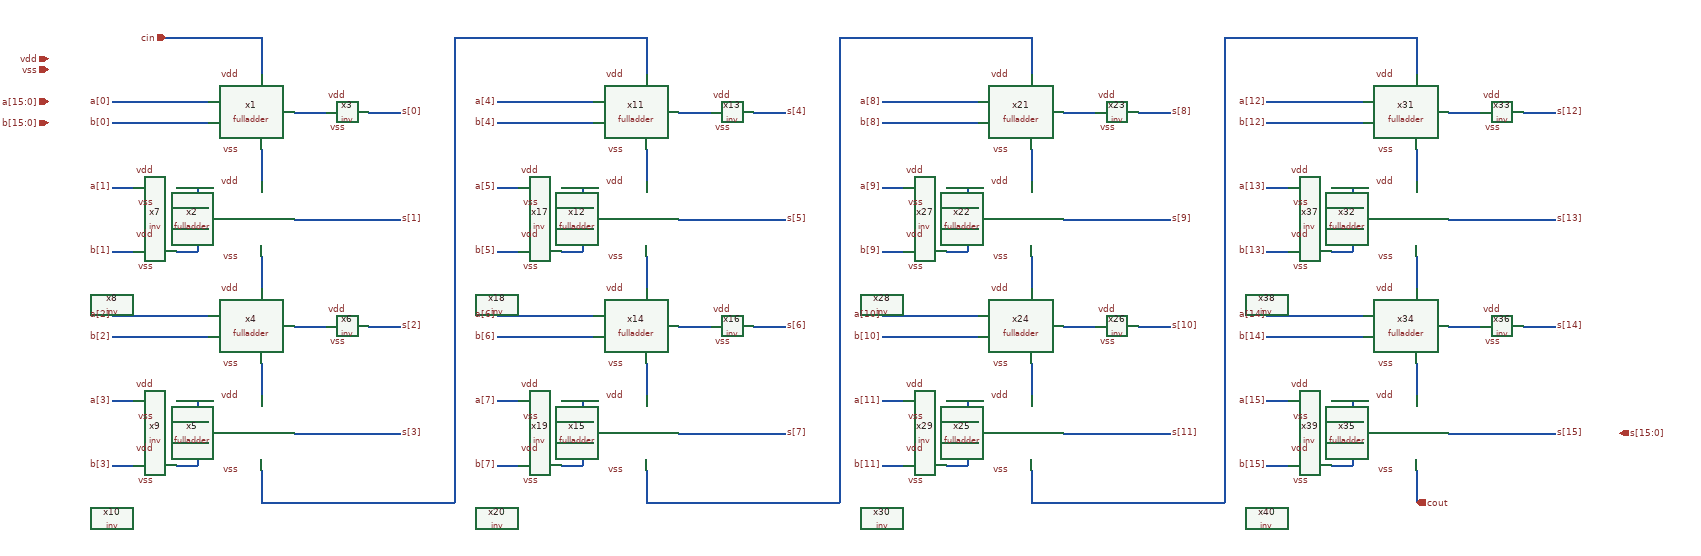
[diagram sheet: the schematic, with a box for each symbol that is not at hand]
v {xschem version=3.4.5 file_version=1.2
}
G {}
K {}
V {}
S {}
E {}
N 300 -460 300 -390 {
lab=cin}
N 120 -460 300 -460 {
lab=cin}
N 360 -320 420 -320 {
lab=#net1}
N 500 -320 560 -320 {
lab=#net2}
N 360 80 420 80 {
lab=#net3}
N 500 80 560 80 {
lab=#net4}
N 140 -180 180 -180 {
lab=#net5}
N 180 -180 180 -140 {
lab=#net5}
N 180 -140 200 -140 {
lab=#net5}
N 140 -60 180 -60 {
lab=#net6}
N 180 -100 180 -60 {
lab=#net6}
N 180 -100 200 -100 {
lab=#net6}
N 20 -60 60 -60 {
lab=a[1]}
N 20 -180 60 -180 {
lab=a[1]}
N 140 220 180 220 {
lab=#net7}
N 180 220 180 260 {
lab=#net7}
N 180 260 200 260 {
lab=#net7}
N 140 340 180 340 {
lab=#net8}
N 180 300 180 340 {
lab=#net8}
N 180 300 200 300 {
lab=#net8}
N 20 340 60 340 {
lab=a[3]}
N 20 220 60 220 {
lab=a[3]}
N 300 -250 300 -190 {
lab=#net9}
N 300 -50 300 10 {
lab=#net10}
N 300 150 300 210 {
lab=#net11}
N 300 350 300 410 {
lab=#net12}
N 20 60 200 60 {
lab=a[2]}
N 20 100 200 100 {
lab=a[2]}
N 20 -340 200 -340 {
lab=a[0]}
N 20 -300 200 -300 {
lab=a[0]}
N 360 -120 560 -120 {
lab=#net13}
N 360 280 560 280 {
lab=#net14}
N 1020 -460 1020 -390 {
lab=#net12}
N 1080 -320 1140 -320 {
lab=#net15}
N 1220 -320 1280 -320 {
lab=#net16}
N 1080 80 1140 80 {
lab=#net17}
N 1220 80 1280 80 {
lab=#net18}
N 860 -180 900 -180 {
lab=#net19}
N 900 -180 900 -140 {
lab=#net19}
N 900 -140 920 -140 {
lab=#net19}
N 860 -60 900 -60 {
lab=#net20}
N 900 -100 900 -60 {
lab=#net20}
N 900 -100 920 -100 {
lab=#net20}
N 740 -60 780 -60 {
lab=a[5]}
N 740 -180 780 -180 {
lab=a[5]}
N 860 220 900 220 {
lab=#net21}
N 900 220 900 260 {
lab=#net21}
N 900 260 920 260 {
lab=#net21}
N 860 340 900 340 {
lab=#net22}
N 900 300 900 340 {
lab=#net22}
N 900 300 920 300 {
lab=#net22}
N 740 340 780 340 {
lab=a[7]}
N 740 220 780 220 {
lab=a[7]}
N 1020 -250 1020 -190 {
lab=#net23}
N 1020 -50 1020 10 {
lab=#net24}
N 1020 150 1020 210 {
lab=#net25}
N 1020 350 1020 410 {
lab=#net26}
N 740 60 920 60 {
lab=a[6]}
N 740 100 920 100 {
lab=a[6]}
N 740 -340 920 -340 {
lab=a[4]}
N 740 -300 920 -300 {
lab=a[4]}
N 1080 -120 1280 -120 {
lab=#net27}
N 1080 280 1280 280 {
lab=#net28}
N 300 410 660 410 {
lab=#net12}
N 660 -460 660 410 {
lab=#net12}
N 660 -460 1020 -460 {
lab=#net12}
N 1740 -460 1740 -390 {
lab=#net26}
N 1800 -320 1860 -320 {
lab=#net29}
N 1940 -320 2000 -320 {
lab=#net30}
N 1800 80 1860 80 {
lab=#net31}
N 1940 80 2000 80 {
lab=#net32}
N 1580 -180 1620 -180 {
lab=#net33}
N 1620 -180 1620 -140 {
lab=#net33}
N 1620 -140 1640 -140 {
lab=#net33}
N 1580 -60 1620 -60 {
lab=#net34}
N 1620 -100 1620 -60 {
lab=#net34}
N 1620 -100 1640 -100 {
lab=#net34}
N 1460 -60 1500 -60 {
lab=a[9]}
N 1460 -180 1500 -180 {
lab=a[9]}
N 1580 220 1620 220 {
lab=#net35}
N 1620 220 1620 260 {
lab=#net35}
N 1620 260 1640 260 {
lab=#net35}
N 1580 340 1620 340 {
lab=#net36}
N 1620 300 1620 340 {
lab=#net36}
N 1620 300 1640 300 {
lab=#net36}
N 1460 340 1500 340 {
lab=#net37}
N 1460 220 1500 220 {
lab=a[11]}
N 1740 -250 1740 -190 {
lab=#net38}
N 1740 -50 1740 10 {
lab=#net39}
N 1740 150 1740 210 {
lab=#net40}
N 1740 350 1740 410 {
lab=#net41}
N 1460 60 1640 60 {
lab=a[10]}
N 1460 100 1640 100 {
lab=a[10]}
N 1460 -340 1640 -340 {
lab=a[8]}
N 1460 -300 1640 -300 {
lab=a[8]}
N 1800 -120 2000 -120 {
lab=#net42}
N 1800 280 2000 280 {
lab=#net43}
N 1020 410 1380 410 {
lab=#net26}
N 1380 -460 1380 410 {
lab=#net26}
N 1380 -460 1740 -460 {
lab=#net26}
N 2460 -460 2460 -390 {
lab=#net41}
N 2520 -320 2580 -320 {
lab=#net44}
N 2660 -320 2720 -320 {
lab=#net45}
N 2520 80 2580 80 {
lab=#net46}
N 2660 80 2720 80 {
lab=#net47}
N 2300 -180 2340 -180 {
lab=#net48}
N 2340 -180 2340 -140 {
lab=#net48}
N 2340 -140 2360 -140 {
lab=#net48}
N 2300 -60 2340 -60 {
lab=#net49}
N 2340 -100 2340 -60 {
lab=#net49}
N 2340 -100 2360 -100 {
lab=#net49}
N 2180 -60 2220 -60 {
lab=#net50}
N 2180 -180 2220 -180 {
lab=a[13]}
N 2300 220 2340 220 {
lab=#net51}
N 2340 220 2340 260 {
lab=#net51}
N 2340 260 2360 260 {
lab=#net51}
N 2300 340 2340 340 {
lab=#net52}
N 2340 300 2340 340 {
lab=#net52}
N 2340 300 2360 300 {
lab=#net52}
N 2180 340 2220 340 {
lab=#net53}
N 2180 220 2220 220 {
lab=a[15]}
N 2460 -250 2460 -190 {
lab=#net54}
N 2460 -50 2460 10 {
lab=#net55}
N 2460 150 2460 210 {
lab=#net56}
N 2460 350 2460 410 {
lab=cout}
N 2180 60 2360 60 {
lab=a[14]}
N 2180 100 2360 100 {
lab=#net57}
N 2180 -340 2360 -340 {
lab=a[12]}
N 2180 -300 2360 -300 {
lab=#net58}
N 2520 -120 2720 -120 {
lab=#net59}
N 2520 280 2720 280 {
lab=#net60}
N 1740 410 2100 410 {
lab=#net41}
N 2100 -460 2100 410 {
lab=#net41}
N 2100 -460 2460 -460 {
lab=#net41}
C {fulladder.sym} 270 -320 0 0 {name=x1}
C {fulladder.sym} 270 -120 0 0 {name=x2}
C {inv.sym} 380 -220 0 0 {name=x3}
C {fulladder.sym} 270 80 0 0 {name=x4}
C {fulladder.sym} 270 280 0 0 {name=x5}
C {inv.sym} 380 180 0 0 {name=x6}
C {inv.sym} 20 -80 0 0 {name=x7}
C {inv.sym} 20 40 0 0 {name=x8}
C {inv.sym} 20 320 0 0 {name=x9}
C {inv.sym} 20 440 0 0 {name=x10}
C {lab_pin.sym} 260 -250 2 1 {name=p2 sig_type=std_logic lab=vss}
C {lab_pin.sym} 260 -390 2 1 {name=p1 sig_type=std_logic lab=vdd}
C {lab_pin.sym} 460 -290 2 1 {name=p3 sig_type=std_logic lab=vss}
C {lab_pin.sym} 460 -350 2 1 {name=p4 sig_type=std_logic lab=vdd}
C {lab_pin.sym} 100 -210 2 1 {name=p5 sig_type=std_logic lab=vdd}
C {lab_pin.sym} 100 -90 2 1 {name=p6 sig_type=std_logic lab=vdd}
C {lab_pin.sym} 100 -150 2 1 {name=p7 sig_type=std_logic lab=vss}
C {lab_pin.sym} 100 -30 2 1 {name=p8 sig_type=std_logic lab=vss}
C {lab_pin.sym} 260 -50 2 1 {name=p9 sig_type=std_logic lab=vss}
C {lab_pin.sym} 260 -190 2 1 {name=p10 sig_type=std_logic lab=vdd}
C {lab_pin.sym} 260 150 2 1 {name=p11 sig_type=std_logic lab=vss}
C {lab_pin.sym} 260 10 2 1 {name=p12 sig_type=std_logic lab=vdd}
C {lab_pin.sym} 460 110 2 1 {name=p13 sig_type=std_logic lab=vss}
C {lab_pin.sym} 460 50 2 1 {name=p14 sig_type=std_logic lab=vdd}
C {lab_pin.sym} 100 190 2 1 {name=p15 sig_type=std_logic lab=vdd}
C {lab_pin.sym} 100 310 2 1 {name=p16 sig_type=std_logic lab=vdd}
C {lab_pin.sym} 100 250 2 1 {name=p17 sig_type=std_logic lab=vss}
C {lab_pin.sym} 100 370 2 1 {name=p18 sig_type=std_logic lab=vss}
C {lab_pin.sym} 260 350 2 1 {name=p19 sig_type=std_logic lab=vss}
C {lab_pin.sym} 260 210 2 1 {name=p20 sig_type=std_logic lab=vdd}
C {fulladder.sym} 990 -320 0 0 {name=x11}
C {fulladder.sym} 990 -120 0 0 {name=x12}
C {inv.sym} 1100 -220 0 0 {name=x13}
C {fulladder.sym} 990 80 0 0 {name=x14}
C {fulladder.sym} 990 280 0 0 {name=x15}
C {inv.sym} 1100 180 0 0 {name=x16}
C {inv.sym} 740 -80 0 0 {name=x17}
C {inv.sym} 740 40 0 0 {name=x18}
C {inv.sym} 740 320 0 0 {name=x19}
C {inv.sym} 740 440 0 0 {name=x20}
C {lab_pin.sym} 980 -250 2 1 {name=p21 sig_type=std_logic lab=vss}
C {lab_pin.sym} 980 -390 2 1 {name=p22 sig_type=std_logic lab=vdd}
C {lab_pin.sym} 1180 -290 2 1 {name=p23 sig_type=std_logic lab=vss}
C {lab_pin.sym} 1180 -350 2 1 {name=p24 sig_type=std_logic lab=vdd}
C {lab_pin.sym} 820 -210 2 1 {name=p25 sig_type=std_logic lab=vdd}
C {lab_pin.sym} 820 -90 2 1 {name=p26 sig_type=std_logic lab=vdd}
C {lab_pin.sym} 820 -150 2 1 {name=p27 sig_type=std_logic lab=vss}
C {lab_pin.sym} 820 -30 2 1 {name=p28 sig_type=std_logic lab=vss}
C {lab_pin.sym} 980 -50 2 1 {name=p29 sig_type=std_logic lab=vss}
C {lab_pin.sym} 980 -190 2 1 {name=p30 sig_type=std_logic lab=vdd}
C {lab_pin.sym} 980 150 2 1 {name=p31 sig_type=std_logic lab=vss}
C {lab_pin.sym} 980 10 2 1 {name=p32 sig_type=std_logic lab=vdd}
C {lab_pin.sym} 1180 110 2 1 {name=p33 sig_type=std_logic lab=vss}
C {lab_pin.sym} 1180 50 2 1 {name=p34 sig_type=std_logic lab=vdd}
C {lab_pin.sym} 820 190 2 1 {name=p35 sig_type=std_logic lab=vdd}
C {lab_pin.sym} 820 310 2 1 {name=p36 sig_type=std_logic lab=vdd}
C {lab_pin.sym} 820 250 2 1 {name=p37 sig_type=std_logic lab=vss}
C {lab_pin.sym} 820 370 2 1 {name=p38 sig_type=std_logic lab=vss}
C {lab_pin.sym} 980 350 2 1 {name=p39 sig_type=std_logic lab=vss}
C {lab_pin.sym} 980 210 2 1 {name=p40 sig_type=std_logic lab=vdd}
C {fulladder.sym} 1710 -320 0 0 {name=x21}
C {fulladder.sym} 1710 -120 0 0 {name=x22}
C {inv.sym} 1820 -220 0 0 {name=x23}
C {fulladder.sym} 1710 80 0 0 {name=x24}
C {fulladder.sym} 1710 280 0 0 {name=x25}
C {inv.sym} 1820 180 0 0 {name=x26}
C {inv.sym} 1460 -80 0 0 {name=x27}
C {inv.sym} 1460 40 0 0 {name=x28}
C {inv.sym} 1460 320 0 0 {name=x29}
C {inv.sym} 1460 440 0 0 {name=x30}
C {lab_pin.sym} 1700 -250 2 1 {name=p41 sig_type=std_logic lab=vss}
C {lab_pin.sym} 1700 -390 2 1 {name=p42 sig_type=std_logic lab=vdd}
C {lab_pin.sym} 1900 -290 2 1 {name=p43 sig_type=std_logic lab=vss}
C {lab_pin.sym} 1900 -350 2 1 {name=p44 sig_type=std_logic lab=vdd}
C {lab_pin.sym} 1540 -210 2 1 {name=p45 sig_type=std_logic lab=vdd}
C {lab_pin.sym} 1540 -90 2 1 {name=p46 sig_type=std_logic lab=vdd}
C {lab_pin.sym} 1540 -150 2 1 {name=p47 sig_type=std_logic lab=vss}
C {lab_pin.sym} 1540 -30 2 1 {name=p48 sig_type=std_logic lab=vss}
C {lab_pin.sym} 1700 -50 2 1 {name=p49 sig_type=std_logic lab=vss}
C {lab_pin.sym} 1700 -190 2 1 {name=p50 sig_type=std_logic lab=vdd}
C {lab_pin.sym} 1700 150 2 1 {name=p51 sig_type=std_logic lab=vss}
C {lab_pin.sym} 1700 10 2 1 {name=p52 sig_type=std_logic lab=vdd}
C {lab_pin.sym} 1900 110 2 1 {name=p53 sig_type=std_logic lab=vss}
C {lab_pin.sym} 1900 50 2 1 {name=p54 sig_type=std_logic lab=vdd}
C {lab_pin.sym} 1540 190 2 1 {name=p55 sig_type=std_logic lab=vdd}
C {lab_pin.sym} 1540 310 2 1 {name=p56 sig_type=std_logic lab=vdd}
C {lab_pin.sym} 1540 250 2 1 {name=p57 sig_type=std_logic lab=vss}
C {lab_pin.sym} 1540 370 2 1 {name=p58 sig_type=std_logic lab=vss}
C {lab_pin.sym} 1700 350 2 1 {name=p59 sig_type=std_logic lab=vss}
C {lab_pin.sym} 1700 210 2 1 {name=p60 sig_type=std_logic lab=vdd}
C {fulladder.sym} 2430 -320 0 0 {name=x31}
C {fulladder.sym} 2430 -120 0 0 {name=x32}
C {inv.sym} 2540 -220 0 0 {name=x33}
C {fulladder.sym} 2430 80 0 0 {name=x34}
C {fulladder.sym} 2430 280 0 0 {name=x35}
C {inv.sym} 2540 180 0 0 {name=x36}
C {inv.sym} 2180 -80 0 0 {name=x37}
C {inv.sym} 2180 40 0 0 {name=x38}
C {inv.sym} 2180 320 0 0 {name=x39}
C {inv.sym} 2180 440 0 0 {name=x40}
C {lab_pin.sym} 2420 -250 2 1 {name=p61 sig_type=std_logic lab=vss}
C {lab_pin.sym} 2420 -390 2 1 {name=p62 sig_type=std_logic lab=vdd}
C {lab_pin.sym} 2620 -290 2 1 {name=p63 sig_type=std_logic lab=vss}
C {lab_pin.sym} 2620 -350 2 1 {name=p64 sig_type=std_logic lab=vdd}
C {lab_pin.sym} 2260 -210 2 1 {name=p65 sig_type=std_logic lab=vdd}
C {lab_pin.sym} 2260 -90 2 1 {name=p66 sig_type=std_logic lab=vdd}
C {lab_pin.sym} 2260 -150 2 1 {name=p67 sig_type=std_logic lab=vss}
C {lab_pin.sym} 2260 -30 2 1 {name=p68 sig_type=std_logic lab=vss}
C {lab_pin.sym} 2420 -50 2 1 {name=p69 sig_type=std_logic lab=vss}
C {lab_pin.sym} 2420 -190 2 1 {name=p70 sig_type=std_logic lab=vdd}
C {lab_pin.sym} 2420 150 2 1 {name=p71 sig_type=std_logic lab=vss}
C {lab_pin.sym} 2420 10 2 1 {name=p72 sig_type=std_logic lab=vdd}
C {lab_pin.sym} 2620 110 2 1 {name=p73 sig_type=std_logic lab=vss}
C {lab_pin.sym} 2620 50 2 1 {name=p74 sig_type=std_logic lab=vdd}
C {lab_pin.sym} 2260 190 2 1 {name=p75 sig_type=std_logic lab=vdd}
C {lab_pin.sym} 2260 310 2 1 {name=p76 sig_type=std_logic lab=vdd}
C {lab_pin.sym} 2260 250 2 1 {name=p77 sig_type=std_logic lab=vss}
C {lab_pin.sym} 2260 370 2 1 {name=p78 sig_type=std_logic lab=vss}
C {lab_pin.sym} 2420 350 2 1 {name=p79 sig_type=std_logic lab=vss}
C {lab_pin.sym} 2420 210 2 1 {name=p80 sig_type=std_logic lab=vdd}
C {ipin.sym} 120 -460 0 0 {name=p81 lab=cin}
C {opin.sym} 2460 410 1 0 {name=p82 lab=cout}
C {lab_pin.sym} 20 -340 2 1 {name=p83 sig_type=std_logic lab=a[0]}
C {lab_pin.sym} 20 -180 2 1 {name=p84 sig_type=std_logic lab=a[1]}
C {lab_pin.sym} 20 60 2 1 {name=p85 sig_type=std_logic lab=a[2]}
C {lab_pin.sym} 20 220 2 1 {name=p86 sig_type=std_logic lab=a[3]}
C {lab_pin.sym} 740 -340 2 1 {name=p87 sig_type=std_logic lab=a[4]}
C {lab_pin.sym} 740 -180 2 1 {name=p88 sig_type=std_logic lab=a[5]}
C {lab_pin.sym} 740 60 2 1 {name=p89 sig_type=std_logic lab=a[6]}
C {lab_pin.sym} 740 220 2 1 {name=p90 sig_type=std_logic lab=a[7]}
C {lab_pin.sym} 1460 -340 2 1 {name=p91 sig_type=std_logic lab=a[8]}
C {lab_pin.sym} 1460 -180 2 1 {name=p92 sig_type=std_logic lab=a[9]}
C {lab_pin.sym} 1460 60 2 1 {name=p93 sig_type=std_logic lab=a[10]}
C {lab_pin.sym} 1460 220 2 1 {name=p94 sig_type=std_logic lab=a[11]}
C {lab_pin.sym} 2180 -340 2 1 {name=p95 sig_type=std_logic lab=a[12]}
C {lab_pin.sym} 2180 -180 2 1 {name=p96 sig_type=std_logic lab=a[13]}
C {lab_pin.sym} 2180 60 2 1 {name=p97 sig_type=std_logic lab=a[14]}
C {lab_pin.sym} 2180 220 2 1 {name=p98 sig_type=std_logic lab=a[15]}
C {lab_pin.sym} 20 -300 2 1 {name=p99 sig_type=std_logic lab=b[0]}
C {lab_pin.sym} 20 -60 2 1 {name=p100 sig_type=std_logic lab=b[1]}
C {lab_pin.sym} 20 100 2 1 {name=p101 sig_type=std_logic lab=b[2]}
C {lab_pin.sym} 20 340 2 1 {name=p102 sig_type=std_logic lab=b[3]}
C {lab_pin.sym} 740 -300 2 1 {name=p103 sig_type=std_logic lab=b[4]}
C {lab_pin.sym} 740 -60 2 1 {name=p104 sig_type=std_logic lab=b[5]}
C {lab_pin.sym} 740 100 2 1 {name=p105 sig_type=std_logic lab=b[6]}
C {lab_pin.sym} 740 340 2 1 {name=p106 sig_type=std_logic lab=b[7]}
C {lab_pin.sym} 1460 -300 2 1 {name=p107 sig_type=std_logic lab=b[8]}
C {lab_pin.sym} 1460 -60 2 1 {name=p108 sig_type=std_logic lab=b[9]}
C {lab_pin.sym} 1460 100 2 1 {name=p109 sig_type=std_logic lab=b[10]}
C {lab_pin.sym} 1460 340 2 1 {name=p110 sig_type=std_logic lab=b[11]}
C {lab_pin.sym} 2180 -300 2 1 {name=p111 sig_type=std_logic lab=b[12]}
C {lab_pin.sym} 2180 -60 2 1 {name=p112 sig_type=std_logic lab=b[13]}
C {lab_pin.sym} 2180 100 2 1 {name=p113 sig_type=std_logic lab=b[14]}
C {lab_pin.sym} 2180 340 2 1 {name=p114 sig_type=std_logic lab=b[15]}
C {lab_pin.sym} 560 -320 2 0 {name=p115 sig_type=std_logic lab=s[0]}
C {lab_pin.sym} 560 -120 2 0 {name=p116 sig_type=std_logic lab=s[1]}
C {lab_pin.sym} 560 80 2 0 {name=p117 sig_type=std_logic lab=s[2]}
C {lab_pin.sym} 560 280 2 0 {name=p118 sig_type=std_logic lab=s[3]}
C {lab_pin.sym} 1280 -320 2 0 {name=p119 sig_type=std_logic lab=s[4]}
C {lab_pin.sym} 1280 -120 2 0 {name=p120 sig_type=std_logic lab=s[5]}
C {lab_pin.sym} 1280 80 2 0 {name=p121 sig_type=std_logic lab=s[6]}
C {lab_pin.sym} 1280 280 2 0 {name=p122 sig_type=std_logic lab=s[7]}
C {lab_pin.sym} 2000 -320 2 0 {name=p123 sig_type=std_logic lab=s[8]}
C {lab_pin.sym} 2000 -120 2 0 {name=p124 sig_type=std_logic lab=s[9]}
C {lab_pin.sym} 2000 80 2 0 {name=p125 sig_type=std_logic lab=s[10]}
C {lab_pin.sym} 2000 280 2 0 {name=p126 sig_type=std_logic lab=s[11]}
C {lab_pin.sym} 2720 -320 2 0 {name=p127 sig_type=std_logic lab=s[12]}
C {lab_pin.sym} 2720 -120 2 0 {name=p128 sig_type=std_logic lab=s[13]}
C {lab_pin.sym} 2720 80 2 0 {name=p129 sig_type=std_logic lab=s[14]}
C {lab_pin.sym} 2720 280 2 0 {name=p130 sig_type=std_logic lab=s[15]}
C {ipin.sym} -100 -340 0 0 {name=p131 lab=a[15:0]}
C {ipin.sym} -100 -300 0 0 {name=p132 lab=b[15:0]
}
C {ipin.sym} -100 -420 0 0 {name=p133 lab=vdd}
C {ipin.sym} -100 -400 0 0 {name=p134 lab=vss}
C {opin.sym} 2840 280 0 0 {name=p135 lab=s[15:0]}
